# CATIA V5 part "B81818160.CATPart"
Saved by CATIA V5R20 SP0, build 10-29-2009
Part number: B81818160
Revision: 3
Definition: design
Nomenclature: B81818160
Source: made
Description: NOT SPECIFIED
Bounding box of the stored display mesh (mm): x -10.833 to 10.833, y -11 to 11, z 0 to 160
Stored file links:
  C:\Users\Raffaele\Desktop\3D X SITO CF\BOLEX\6-PILLAR REF 818\B81818160.CATPart

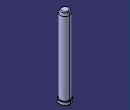
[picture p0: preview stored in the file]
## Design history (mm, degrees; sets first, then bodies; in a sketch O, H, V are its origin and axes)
Body1 "MANIFOLD_SOLID_BREP #370" (main body)
  Solid1: solid without history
